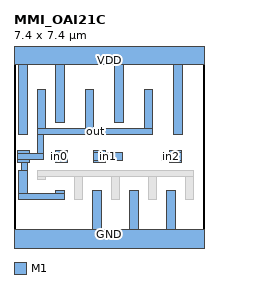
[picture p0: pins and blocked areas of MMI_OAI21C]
MACRO MMI_OAI21C
	CLASS CORE ;
	FOREIGN MMI_OAI21C 0 0 ;
	SIZE 7.4 BY 7.4 ;
	SYMMETRY X Y ;
	SITE CORE1 ;
	PIN out
		DIRECTION output ;
		USE SIGNAL ;
		PORT
			LAYER M1 ;
			RECT 0.9 4.415 1.24 5.945 ;
			LAYER M1 ;
			RECT 2.77 4.415 3.11 5.945 ;
			LAYER M1 ;
			RECT 5.07 4.415 5.41 5.945 ;
			LAYER M1 ;
			RECT 0.9 4.185 5.41 4.415 ;
			LAYER M1 ;
			RECT 0.145 3.445 0.595 3.555 ;
			LAYER M1 ;
			RECT 0.9 3.445 1.13 4.185 ;
			LAYER M1 ;
			RECT 0.145 3.215 1.13 3.445 ;
			LAYER M1 ;
			RECT 0.145 3.105 0.595 3.215 ;
			LAYER M1 ;
			RECT 0.29 2.795 0.52 3.105 ;
			LAYER M1 ;
			RECT 0.18 1.88 0.52 2.795 ;
			LAYER M1 ;
			RECT 1.62 1.88 1.96 1.99 ;
			LAYER M1 ;
			RECT 0.18 1.65 1.96 1.88 ;
		END
		AntennaDiffArea 4.2303 ;
	END out
	PIN in1
		DIRECTION input ;
		USE SIGNAL ;
		PORT
			LAYER M1 ;
			RECT 3.105 3.495 3.555 3.555 ;
			LAYER M1 ;
			RECT 3.105 3.155 4.24 3.495 ;
			LAYER M1 ;
			RECT 3.105 3.105 3.555 3.155 ;
		END
		AntennaGateArea 1.9863 ;
	END in1
	PIN GND
		DIRECTION inout ;
		USE GROUND ;
		PORT
			LAYER M1 ;
			RECT 3.06 0.5 3.4 1.99 ;
			LAYER M1 ;
			RECT 4.5 0.5 4.84 1.99 ;
			LAYER M1 ;
			RECT 5.94 0.5 6.28 1.99 ;
			LAYER M1 ;
			RECT 0 -0.5 7.4 0.5 ;
		END
	END GND
	PIN in2
		DIRECTION input ;
		USE SIGNAL ;
		PORT
			LAYER M1 ;
			RECT 6.065 3.495 6.515 3.555 ;
			LAYER M1 ;
			RECT 5.74 3.155 6.515 3.495 ;
			LAYER M1 ;
			RECT 6.065 3.105 6.515 3.155 ;
		END
		AntennaGateArea 1.9863 ;
	END in2
	PIN VDD
		DIRECTION inout ;
		USE POWER ;
		PORT
			LAYER M1 ;
			RECT 0 6.9 7.4 7.9 ;
			LAYER M1 ;
			RECT 0.18 4.185 0.52 6.9 ;
			LAYER M1 ;
			RECT 1.62 4.665 1.96 6.9 ;
			LAYER M1 ;
			RECT 3.92 4.665 4.26 6.9 ;
			LAYER M1 ;
			RECT 6.22 4.185 6.56 6.9 ;
		END
	END VDD
	PIN in0
		DIRECTION input ;
		USE SIGNAL ;
		PORT
			LAYER M1 ;
			RECT 1.625 3.495 2.075 3.555 ;
			LAYER M1 ;
			RECT 1.43 3.155 2.075 3.495 ;
			LAYER M1 ;
			RECT 1.625 3.105 2.075 3.155 ;
		END
		AntennaGateArea 1.3239 ;
	END in0
	OBS
		LAYER M1 ;
		RECT 0.9 2.565 7 2.795 ;
		LAYER M1 ;
		RECT 0.9 2.45 1.24 2.565 ;
		LAYER M1 ;
		RECT 2.34 1.65 2.68 2.565 ;
		LAYER M1 ;
		RECT 3.78 1.65 4.12 2.565 ;
		LAYER M1 ;
		RECT 5.22 1.65 5.56 2.565 ;
		LAYER M1 ;
		RECT 6.66 1.65 7 2.565 ;
	END
END MMI_OAI21C
